VERSION 5.7 ;
  NOWIREEXTENSIONATPIN ON ;
  DIVIDERCHAR "/" ;
  BUSBITCHARS "[]" ;
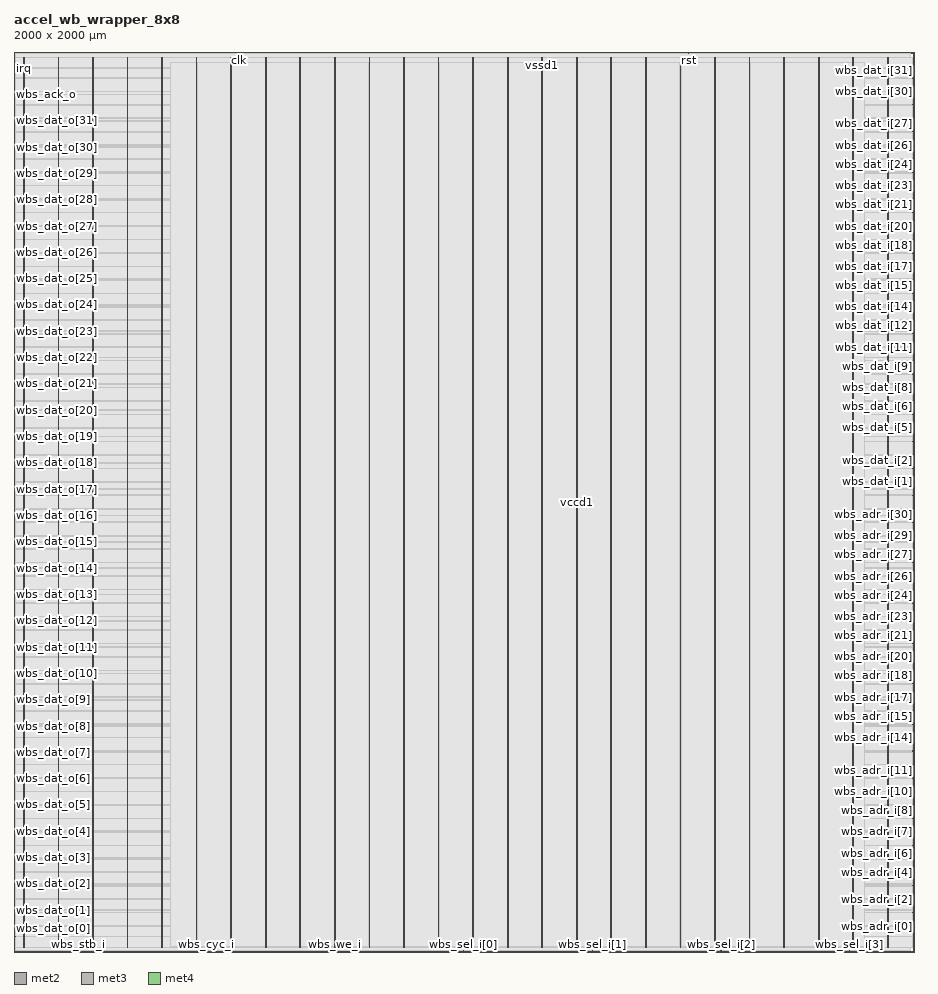
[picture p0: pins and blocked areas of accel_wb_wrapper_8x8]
MACRO accel_wb_wrapper_8x8
  CLASS BLOCK ;
  FOREIGN accel_wb_wrapper_8x8 ;
  ORIGIN 0.000 0.000 ;
  SIZE 2000.000 BY 2000.000 ;
  PIN clk
    DIRECTION INPUT ;
    USE SIGNAL ;
    ANTENNAGATEAREA 0.852000 ;
    ANTENNADIFFAREA 0.869400 ;
    PORT
      LAYER met2 ;
        RECT 499.650 1996.000 499.930 2000.000 ;
    END
  END clk
  PIN irq
    DIRECTION OUTPUT ;
    USE SIGNAL ;
    PORT
      LAYER met3 ;
        RECT 0.000 1963.880 4.000 1964.480 ;
    END
  END irq
  PIN rst
    DIRECTION INPUT ;
    USE SIGNAL ;
    ANTENNAGATEAREA 0.247500 ;
    PORT
      LAYER met2 ;
        RECT 1499.690 1996.000 1499.970 2000.000 ;
    END
  END rst
  PIN vccd1
    DIRECTION INOUT ;
    USE POWER ;
    PORT
      LAYER met4 ;
        RECT 21.040 10.640 22.640 1988.560 ;
    END
    PORT
      LAYER met4 ;
        RECT 174.640 10.640 176.240 1988.560 ;
    END
    PORT
      LAYER met4 ;
        RECT 328.240 10.640 329.840 1988.560 ;
    END
    PORT
      LAYER met4 ;
        RECT 481.840 10.640 483.440 1988.560 ;
    END
    PORT
      LAYER met4 ;
        RECT 635.440 10.640 637.040 1988.560 ;
    END
    PORT
      LAYER met4 ;
        RECT 789.040 10.640 790.640 1988.560 ;
    END
    PORT
      LAYER met4 ;
        RECT 942.640 10.640 944.240 1988.560 ;
    END
    PORT
      LAYER met4 ;
        RECT 1096.240 10.640 1097.840 1988.560 ;
    END
    PORT
      LAYER met4 ;
        RECT 1249.840 10.640 1251.440 1988.560 ;
    END
    PORT
      LAYER met4 ;
        RECT 1403.440 10.640 1405.040 1988.560 ;
    END
    PORT
      LAYER met4 ;
        RECT 1557.040 10.640 1558.640 1988.560 ;
    END
    PORT
      LAYER met4 ;
        RECT 1710.640 10.640 1712.240 1988.560 ;
    END
    PORT
      LAYER met4 ;
        RECT 1864.240 10.640 1865.840 1988.560 ;
    END
  END vccd1
  PIN vssd1
    DIRECTION INOUT ;
    USE GROUND ;
    PORT
      LAYER met4 ;
        RECT 97.840 10.640 99.440 1988.560 ;
    END
    PORT
      LAYER met4 ;
        RECT 251.440 10.640 253.040 1988.560 ;
    END
    PORT
      LAYER met4 ;
        RECT 405.040 10.640 406.640 1988.560 ;
    END
    PORT
      LAYER met4 ;
        RECT 558.640 10.640 560.240 1988.560 ;
    END
    PORT
      LAYER met4 ;
        RECT 712.240 10.640 713.840 1988.560 ;
    END
    PORT
      LAYER met4 ;
        RECT 865.840 10.640 867.440 1988.560 ;
    END
    PORT
      LAYER met4 ;
        RECT 1019.440 10.640 1021.040 1988.560 ;
    END
    PORT
      LAYER met4 ;
        RECT 1173.040 10.640 1174.640 1988.560 ;
    END
    PORT
      LAYER met4 ;
        RECT 1326.640 10.640 1328.240 1988.560 ;
    END
    PORT
      LAYER met4 ;
        RECT 1480.240 10.640 1481.840 1988.560 ;
    END
    PORT
      LAYER met4 ;
        RECT 1633.840 10.640 1635.440 1988.560 ;
    END
    PORT
      LAYER met4 ;
        RECT 1787.440 10.640 1789.040 1988.560 ;
    END
    PORT
      LAYER met4 ;
        RECT 1941.040 10.640 1942.640 1988.560 ;
    END
  END vssd1
  PIN wbs_ack_o
    DIRECTION OUTPUT ;
    USE SIGNAL ;
    ANTENNADIFFAREA 1.782000 ;
    PORT
      LAYER met3 ;
        RECT 0.000 1905.400 4.000 1906.000 ;
    END
  END wbs_ack_o
  PIN wbs_adr_i[0]
    DIRECTION INPUT ;
    USE SIGNAL ;
    ANTENNAGATEAREA 0.742500 ;
    PORT
      LAYER met3 ;
        RECT 1996.000 57.160 2000.000 57.760 ;
    END
  END wbs_adr_i[0]
  PIN wbs_adr_i[10]
    DIRECTION INPUT ;
    USE SIGNAL ;
    ANTENNAGATEAREA 0.196500 ;
    PORT
      LAYER met3 ;
        RECT 1996.000 356.360 2000.000 356.960 ;
    END
  END wbs_adr_i[10]
  PIN wbs_adr_i[11]
    DIRECTION INPUT ;
    USE SIGNAL ;
    ANTENNAGATEAREA 0.196500 ;
    PORT
      LAYER met3 ;
        RECT 1996.000 386.280 2000.000 386.880 ;
    END
  END wbs_adr_i[11]
  PIN wbs_adr_i[12]
    DIRECTION INPUT ;
    USE SIGNAL ;
    ANTENNAGATEAREA 0.196500 ;
    PORT
      LAYER met3 ;
        RECT 1996.000 416.200 2000.000 416.800 ;
    END
  END wbs_adr_i[12]
  PIN wbs_adr_i[13]
    DIRECTION INPUT ;
    USE SIGNAL ;
    ANTENNAGATEAREA 0.196500 ;
    PORT
      LAYER met3 ;
        RECT 1996.000 446.120 2000.000 446.720 ;
    END
  END wbs_adr_i[13]
  PIN wbs_adr_i[14]
    DIRECTION INPUT ;
    USE SIGNAL ;
    ANTENNAGATEAREA 0.196500 ;
    PORT
      LAYER met3 ;
        RECT 1996.000 476.040 2000.000 476.640 ;
    END
  END wbs_adr_i[14]
  PIN wbs_adr_i[15]
    DIRECTION INPUT ;
    USE SIGNAL ;
    ANTENNAGATEAREA 0.196500 ;
    PORT
      LAYER met3 ;
        RECT 1996.000 505.960 2000.000 506.560 ;
    END
  END wbs_adr_i[15]
  PIN wbs_adr_i[16]
    DIRECTION INPUT ;
    USE SIGNAL ;
    ANTENNAGATEAREA 0.196500 ;
    PORT
      LAYER met3 ;
        RECT 1996.000 535.880 2000.000 536.480 ;
    END
  END wbs_adr_i[16]
  PIN wbs_adr_i[17]
    DIRECTION INPUT ;
    USE SIGNAL ;
    ANTENNAGATEAREA 0.196500 ;
    PORT
      LAYER met3 ;
        RECT 1996.000 565.800 2000.000 566.400 ;
    END
  END wbs_adr_i[17]
  PIN wbs_adr_i[18]
    DIRECTION INPUT ;
    USE SIGNAL ;
    ANTENNAGATEAREA 0.196500 ;
    PORT
      LAYER met3 ;
        RECT 1996.000 595.720 2000.000 596.320 ;
    END
  END wbs_adr_i[18]
  PIN wbs_adr_i[19]
    DIRECTION INPUT ;
    USE SIGNAL ;
    ANTENNAGATEAREA 0.196500 ;
    PORT
      LAYER met3 ;
        RECT 1996.000 625.640 2000.000 626.240 ;
    END
  END wbs_adr_i[19]
  PIN wbs_adr_i[1]
    DIRECTION INPUT ;
    USE SIGNAL ;
    ANTENNAGATEAREA 0.495000 ;
    PORT
      LAYER met3 ;
        RECT 1996.000 87.080 2000.000 87.680 ;
    END
  END wbs_adr_i[1]
  PIN wbs_adr_i[20]
    DIRECTION INPUT ;
    USE SIGNAL ;
    ANTENNAGATEAREA 0.196500 ;
    PORT
      LAYER met3 ;
        RECT 1996.000 655.560 2000.000 656.160 ;
    END
  END wbs_adr_i[20]
  PIN wbs_adr_i[21]
    DIRECTION INPUT ;
    USE SIGNAL ;
    ANTENNAGATEAREA 0.196500 ;
    PORT
      LAYER met3 ;
        RECT 1996.000 685.480 2000.000 686.080 ;
    END
  END wbs_adr_i[21]
  PIN wbs_adr_i[22]
    DIRECTION INPUT ;
    USE SIGNAL ;
    ANTENNAGATEAREA 0.196500 ;
    PORT
      LAYER met3 ;
        RECT 1996.000 715.400 2000.000 716.000 ;
    END
  END wbs_adr_i[22]
  PIN wbs_adr_i[23]
    DIRECTION INPUT ;
    USE SIGNAL ;
    ANTENNAGATEAREA 0.196500 ;
    PORT
      LAYER met3 ;
        RECT 1996.000 745.320 2000.000 745.920 ;
    END
  END wbs_adr_i[23]
  PIN wbs_adr_i[24]
    DIRECTION INPUT ;
    USE SIGNAL ;
    ANTENNAGATEAREA 0.196500 ;
    PORT
      LAYER met3 ;
        RECT 1996.000 775.240 2000.000 775.840 ;
    END
  END wbs_adr_i[24]
  PIN wbs_adr_i[25]
    DIRECTION INPUT ;
    USE SIGNAL ;
    ANTENNAGATEAREA 0.196500 ;
    PORT
      LAYER met3 ;
        RECT 1996.000 805.160 2000.000 805.760 ;
    END
  END wbs_adr_i[25]
  PIN wbs_adr_i[26]
    DIRECTION INPUT ;
    USE SIGNAL ;
    ANTENNAGATEAREA 0.196500 ;
    PORT
      LAYER met3 ;
        RECT 1996.000 835.080 2000.000 835.680 ;
    END
  END wbs_adr_i[26]
  PIN wbs_adr_i[27]
    DIRECTION INPUT ;
    USE SIGNAL ;
    ANTENNAGATEAREA 0.196500 ;
    PORT
      LAYER met3 ;
        RECT 1996.000 865.000 2000.000 865.600 ;
    END
  END wbs_adr_i[27]
  PIN wbs_adr_i[28]
    DIRECTION INPUT ;
    USE SIGNAL ;
    ANTENNAGATEAREA 0.196500 ;
    PORT
      LAYER met3 ;
        RECT 1996.000 894.920 2000.000 895.520 ;
    END
  END wbs_adr_i[28]
  PIN wbs_adr_i[29]
    DIRECTION INPUT ;
    USE SIGNAL ;
    ANTENNAGATEAREA 0.213000 ;
    PORT
      LAYER met3 ;
        RECT 1996.000 924.840 2000.000 925.440 ;
    END
  END wbs_adr_i[29]
  PIN wbs_adr_i[2]
    DIRECTION INPUT ;
    USE SIGNAL ;
    ANTENNAGATEAREA 0.495000 ;
    PORT
      LAYER met3 ;
        RECT 1996.000 117.000 2000.000 117.600 ;
    END
  END wbs_adr_i[2]
  PIN wbs_adr_i[30]
    DIRECTION INPUT ;
    USE SIGNAL ;
    ANTENNAGATEAREA 0.247500 ;
    PORT
      LAYER met3 ;
        RECT 1996.000 954.760 2000.000 955.360 ;
    END
  END wbs_adr_i[30]
  PIN wbs_adr_i[31]
    DIRECTION INPUT ;
    USE SIGNAL ;
    ANTENNAGATEAREA 0.247500 ;
    PORT
      LAYER met3 ;
        RECT 1996.000 984.680 2000.000 985.280 ;
    END
  END wbs_adr_i[31]
  PIN wbs_adr_i[3]
    DIRECTION INPUT ;
    USE SIGNAL ;
    ANTENNAGATEAREA 0.495000 ;
    PORT
      LAYER met3 ;
        RECT 1996.000 146.920 2000.000 147.520 ;
    END
  END wbs_adr_i[3]
  PIN wbs_adr_i[4]
    DIRECTION INPUT ;
    USE SIGNAL ;
    ANTENNAGATEAREA 0.426000 ;
    PORT
      LAYER met3 ;
        RECT 1996.000 176.840 2000.000 177.440 ;
    END
  END wbs_adr_i[4]
  PIN wbs_adr_i[5]
    DIRECTION INPUT ;
    USE SIGNAL ;
    ANTENNAGATEAREA 0.426000 ;
    PORT
      LAYER met3 ;
        RECT 1996.000 206.760 2000.000 207.360 ;
    END
  END wbs_adr_i[5]
  PIN wbs_adr_i[6]
    DIRECTION INPUT ;
    USE SIGNAL ;
    ANTENNAGATEAREA 0.742500 ;
    PORT
      LAYER met3 ;
        RECT 1996.000 236.680 2000.000 237.280 ;
    END
  END wbs_adr_i[6]
  PIN wbs_adr_i[7]
    DIRECTION INPUT ;
    USE SIGNAL ;
    ANTENNAGATEAREA 0.742500 ;
    PORT
      LAYER met3 ;
        RECT 1996.000 266.600 2000.000 267.200 ;
    END
  END wbs_adr_i[7]
  PIN wbs_adr_i[8]
    DIRECTION INPUT ;
    USE SIGNAL ;
    ANTENNAGATEAREA 0.196500 ;
    PORT
      LAYER met3 ;
        RECT 1996.000 296.520 2000.000 297.120 ;
    END
  END wbs_adr_i[8]
  PIN wbs_adr_i[9]
    DIRECTION INPUT ;
    USE SIGNAL ;
    ANTENNAGATEAREA 0.196500 ;
    PORT
      LAYER met3 ;
        RECT 1996.000 326.440 2000.000 327.040 ;
    END
  END wbs_adr_i[9]
  PIN wbs_cyc_i
    DIRECTION INPUT ;
    USE SIGNAL ;
    ANTENNAGATEAREA 0.196500 ;
    PORT
      LAYER met2 ;
        RECT 428.350 0.000 428.630 4.000 ;
    END
  END wbs_cyc_i
  PIN wbs_dat_i[0]
    DIRECTION INPUT ;
    USE SIGNAL ;
    ANTENNAGATEAREA 0.196500 ;
    PORT
      LAYER met3 ;
        RECT 1996.000 1014.600 2000.000 1015.200 ;
    END
  END wbs_dat_i[0]
  PIN wbs_dat_i[10]
    DIRECTION INPUT ;
    USE SIGNAL ;
    ANTENNAGATEAREA 0.159000 ;
    PORT
      LAYER met3 ;
        RECT 1996.000 1313.800 2000.000 1314.400 ;
    END
  END wbs_dat_i[10]
  PIN wbs_dat_i[11]
    DIRECTION INPUT ;
    USE SIGNAL ;
    ANTENNAGATEAREA 0.159000 ;
    PORT
      LAYER met3 ;
        RECT 1996.000 1343.720 2000.000 1344.320 ;
    END
  END wbs_dat_i[11]
  PIN wbs_dat_i[12]
    DIRECTION INPUT ;
    USE SIGNAL ;
    ANTENNAGATEAREA 0.247500 ;
    PORT
      LAYER met3 ;
        RECT 1996.000 1373.640 2000.000 1374.240 ;
    END
  END wbs_dat_i[12]
  PIN wbs_dat_i[13]
    DIRECTION INPUT ;
    USE SIGNAL ;
    ANTENNAGATEAREA 0.213000 ;
    PORT
      LAYER met3 ;
        RECT 1996.000 1403.560 2000.000 1404.160 ;
    END
  END wbs_dat_i[13]
  PIN wbs_dat_i[14]
    DIRECTION INPUT ;
    USE SIGNAL ;
    ANTENNAGATEAREA 0.247500 ;
    PORT
      LAYER met3 ;
        RECT 1996.000 1433.480 2000.000 1434.080 ;
    END
  END wbs_dat_i[14]
  PIN wbs_dat_i[15]
    DIRECTION INPUT ;
    USE SIGNAL ;
    ANTENNAGATEAREA 0.213000 ;
    PORT
      LAYER met3 ;
        RECT 1996.000 1463.400 2000.000 1464.000 ;
    END
  END wbs_dat_i[15]
  PIN wbs_dat_i[16]
    DIRECTION INPUT ;
    USE SIGNAL ;
    ANTENNAGATEAREA 0.426000 ;
    PORT
      LAYER met3 ;
        RECT 1996.000 1493.320 2000.000 1493.920 ;
    END
  END wbs_dat_i[16]
  PIN wbs_dat_i[17]
    DIRECTION INPUT ;
    USE SIGNAL ;
    ANTENNAGATEAREA 0.247500 ;
    PORT
      LAYER met3 ;
        RECT 1996.000 1523.240 2000.000 1523.840 ;
    END
  END wbs_dat_i[17]
  PIN wbs_dat_i[18]
    DIRECTION INPUT ;
    USE SIGNAL ;
    ANTENNAGATEAREA 0.247500 ;
    PORT
      LAYER met3 ;
        RECT 1996.000 1553.160 2000.000 1553.760 ;
    END
  END wbs_dat_i[18]
  PIN wbs_dat_i[19]
    DIRECTION INPUT ;
    USE SIGNAL ;
    ANTENNAGATEAREA 0.247500 ;
    PORT
      LAYER met3 ;
        RECT 1996.000 1583.080 2000.000 1583.680 ;
    END
  END wbs_dat_i[19]
  PIN wbs_dat_i[1]
    DIRECTION INPUT ;
    USE SIGNAL ;
    ANTENNAGATEAREA 0.247500 ;
    PORT
      LAYER met3 ;
        RECT 1996.000 1044.520 2000.000 1045.120 ;
    END
  END wbs_dat_i[1]
  PIN wbs_dat_i[20]
    DIRECTION INPUT ;
    USE SIGNAL ;
    ANTENNAGATEAREA 0.426000 ;
    PORT
      LAYER met3 ;
        RECT 1996.000 1613.000 2000.000 1613.600 ;
    END
  END wbs_dat_i[20]
  PIN wbs_dat_i[21]
    DIRECTION INPUT ;
    USE SIGNAL ;
    ANTENNAGATEAREA 0.247500 ;
    PORT
      LAYER met3 ;
        RECT 1996.000 1642.920 2000.000 1643.520 ;
    END
  END wbs_dat_i[21]
  PIN wbs_dat_i[22]
    DIRECTION INPUT ;
    USE SIGNAL ;
    ANTENNAGATEAREA 0.426000 ;
    PORT
      LAYER met3 ;
        RECT 1996.000 1672.840 2000.000 1673.440 ;
    END
  END wbs_dat_i[22]
  PIN wbs_dat_i[23]
    DIRECTION INPUT ;
    USE SIGNAL ;
    ANTENNAGATEAREA 0.495000 ;
    PORT
      LAYER met3 ;
        RECT 1996.000 1702.760 2000.000 1703.360 ;
    END
  END wbs_dat_i[23]
  PIN wbs_dat_i[24]
    DIRECTION INPUT ;
    USE SIGNAL ;
    ANTENNAGATEAREA 0.247500 ;
    PORT
      LAYER met3 ;
        RECT 1996.000 1732.680 2000.000 1733.280 ;
    END
  END wbs_dat_i[24]
  PIN wbs_dat_i[25]
    DIRECTION INPUT ;
    USE SIGNAL ;
    ANTENNAGATEAREA 0.247500 ;
    PORT
      LAYER met3 ;
        RECT 1996.000 1762.600 2000.000 1763.200 ;
    END
  END wbs_dat_i[25]
  PIN wbs_dat_i[26]
    DIRECTION INPUT ;
    USE SIGNAL ;
    ANTENNAGATEAREA 0.426000 ;
    PORT
      LAYER met3 ;
        RECT 1996.000 1792.520 2000.000 1793.120 ;
    END
  END wbs_dat_i[26]
  PIN wbs_dat_i[27]
    DIRECTION INPUT ;
    USE SIGNAL ;
    ANTENNAGATEAREA 0.247500 ;
    PORT
      LAYER met3 ;
        RECT 1996.000 1822.440 2000.000 1823.040 ;
    END
  END wbs_dat_i[27]
  PIN wbs_dat_i[28]
    DIRECTION INPUT ;
    USE SIGNAL ;
    ANTENNAGATEAREA 0.495000 ;
    PORT
      LAYER met3 ;
        RECT 1996.000 1852.360 2000.000 1852.960 ;
    END
  END wbs_dat_i[28]
  PIN wbs_dat_i[29]
    DIRECTION INPUT ;
    USE SIGNAL ;
    ANTENNAGATEAREA 0.495000 ;
    PORT
      LAYER met3 ;
        RECT 1996.000 1882.280 2000.000 1882.880 ;
    END
  END wbs_dat_i[29]
  PIN wbs_dat_i[2]
    DIRECTION INPUT ;
    USE SIGNAL ;
    ANTENNAGATEAREA 0.247500 ;
    PORT
      LAYER met3 ;
        RECT 1996.000 1074.440 2000.000 1075.040 ;
    END
  END wbs_dat_i[2]
  PIN wbs_dat_i[30]
    DIRECTION INPUT ;
    USE SIGNAL ;
    ANTENNAGATEAREA 0.426000 ;
    PORT
      LAYER met3 ;
        RECT 1996.000 1912.200 2000.000 1912.800 ;
    END
  END wbs_dat_i[30]
  PIN wbs_dat_i[31]
    DIRECTION INPUT ;
    USE SIGNAL ;
    ANTENNAGATEAREA 0.426000 ;
    PORT
      LAYER met3 ;
        RECT 1996.000 1942.120 2000.000 1942.720 ;
    END
  END wbs_dat_i[31]
  PIN wbs_dat_i[3]
    DIRECTION INPUT ;
    USE SIGNAL ;
    ANTENNAGATEAREA 0.247500 ;
    PORT
      LAYER met3 ;
        RECT 1996.000 1104.360 2000.000 1104.960 ;
    END
  END wbs_dat_i[3]
  PIN wbs_dat_i[4]
    DIRECTION INPUT ;
    USE SIGNAL ;
    ANTENNAGATEAREA 0.159000 ;
    PORT
      LAYER met3 ;
        RECT 1996.000 1134.280 2000.000 1134.880 ;
    END
  END wbs_dat_i[4]
  PIN wbs_dat_i[5]
    DIRECTION INPUT ;
    USE SIGNAL ;
    ANTENNAGATEAREA 0.495000 ;
    PORT
      LAYER met3 ;
        RECT 1996.000 1164.200 2000.000 1164.800 ;
    END
  END wbs_dat_i[5]
  PIN wbs_dat_i[6]
    DIRECTION INPUT ;
    USE SIGNAL ;
    ANTENNAGATEAREA 0.159000 ;
    PORT
      LAYER met3 ;
        RECT 1996.000 1194.120 2000.000 1194.720 ;
    END
  END wbs_dat_i[6]
  PIN wbs_dat_i[7]
    DIRECTION INPUT ;
    USE SIGNAL ;
    ANTENNAGATEAREA 0.159000 ;
    PORT
      LAYER met3 ;
        RECT 1996.000 1224.040 2000.000 1224.640 ;
    END
  END wbs_dat_i[7]
  PIN wbs_dat_i[8]
    DIRECTION INPUT ;
    USE SIGNAL ;
    ANTENNAGATEAREA 0.213000 ;
    PORT
      LAYER met3 ;
        RECT 1996.000 1253.960 2000.000 1254.560 ;
    END
  END wbs_dat_i[8]
  PIN wbs_dat_i[9]
    DIRECTION INPUT ;
    USE SIGNAL ;
    ANTENNAGATEAREA 0.213000 ;
    PORT
      LAYER met3 ;
        RECT 1996.000 1283.880 2000.000 1284.480 ;
    END
  END wbs_dat_i[9]
  PIN wbs_dat_o[0]
    DIRECTION OUTPUT ;
    USE SIGNAL ;
    ANTENNADIFFAREA 1.782000 ;
    PORT
      LAYER met3 ;
        RECT 0.000 34.040 4.000 34.640 ;
    END
  END wbs_dat_o[0]
  PIN wbs_dat_o[10]
    DIRECTION OUTPUT ;
    USE SIGNAL ;
    ANTENNADIFFAREA 1.782000 ;
    PORT
      LAYER met3 ;
        RECT 0.000 618.840 4.000 619.440 ;
    END
  END wbs_dat_o[10]
  PIN wbs_dat_o[11]
    DIRECTION OUTPUT ;
    USE SIGNAL ;
    ANTENNADIFFAREA 1.782000 ;
    PORT
      LAYER met3 ;
        RECT 0.000 677.320 4.000 677.920 ;
    END
  END wbs_dat_o[11]
  PIN wbs_dat_o[12]
    DIRECTION OUTPUT ;
    USE SIGNAL ;
    ANTENNADIFFAREA 1.782000 ;
    PORT
      LAYER met3 ;
        RECT 0.000 735.800 4.000 736.400 ;
    END
  END wbs_dat_o[12]
  PIN wbs_dat_o[13]
    DIRECTION OUTPUT ;
    USE SIGNAL ;
    ANTENNADIFFAREA 1.782000 ;
    PORT
      LAYER met3 ;
        RECT 0.000 794.280 4.000 794.880 ;
    END
  END wbs_dat_o[13]
  PIN wbs_dat_o[14]
    DIRECTION OUTPUT ;
    USE SIGNAL ;
    ANTENNADIFFAREA 1.782000 ;
    PORT
      LAYER met3 ;
        RECT 0.000 852.760 4.000 853.360 ;
    END
  END wbs_dat_o[14]
  PIN wbs_dat_o[15]
    DIRECTION OUTPUT ;
    USE SIGNAL ;
    ANTENNADIFFAREA 1.782000 ;
    PORT
      LAYER met3 ;
        RECT 0.000 911.240 4.000 911.840 ;
    END
  END wbs_dat_o[15]
  PIN wbs_dat_o[16]
    DIRECTION OUTPUT ;
    USE SIGNAL ;
    ANTENNADIFFAREA 1.782000 ;
    PORT
      LAYER met3 ;
        RECT 0.000 969.720 4.000 970.320 ;
    END
  END wbs_dat_o[16]
  PIN wbs_dat_o[17]
    DIRECTION OUTPUT ;
    USE SIGNAL ;
    ANTENNADIFFAREA 1.782000 ;
    PORT
      LAYER met3 ;
        RECT 0.000 1028.200 4.000 1028.800 ;
    END
  END wbs_dat_o[17]
  PIN wbs_dat_o[18]
    DIRECTION OUTPUT ;
    USE SIGNAL ;
    ANTENNADIFFAREA 1.782000 ;
    PORT
      LAYER met3 ;
        RECT 0.000 1086.680 4.000 1087.280 ;
    END
  END wbs_dat_o[18]
  PIN wbs_dat_o[19]
    DIRECTION OUTPUT ;
    USE SIGNAL ;
    ANTENNADIFFAREA 1.782000 ;
    PORT
      LAYER met3 ;
        RECT 0.000 1145.160 4.000 1145.760 ;
    END
  END wbs_dat_o[19]
  PIN wbs_dat_o[1]
    DIRECTION OUTPUT ;
    USE SIGNAL ;
    ANTENNADIFFAREA 1.782000 ;
    PORT
      LAYER met3 ;
        RECT 0.000 92.520 4.000 93.120 ;
    END
  END wbs_dat_o[1]
  PIN wbs_dat_o[20]
    DIRECTION OUTPUT ;
    USE SIGNAL ;
    ANTENNADIFFAREA 1.782000 ;
    PORT
      LAYER met3 ;
        RECT 0.000 1203.640 4.000 1204.240 ;
    END
  END wbs_dat_o[20]
  PIN wbs_dat_o[21]
    DIRECTION OUTPUT ;
    USE SIGNAL ;
    ANTENNADIFFAREA 1.782000 ;
    PORT
      LAYER met3 ;
        RECT 0.000 1262.120 4.000 1262.720 ;
    END
  END wbs_dat_o[21]
  PIN wbs_dat_o[22]
    DIRECTION OUTPUT ;
    USE SIGNAL ;
    ANTENNADIFFAREA 1.782000 ;
    PORT
      LAYER met3 ;
        RECT 0.000 1320.600 4.000 1321.200 ;
    END
  END wbs_dat_o[22]
  PIN wbs_dat_o[23]
    DIRECTION OUTPUT ;
    USE SIGNAL ;
    ANTENNADIFFAREA 1.782000 ;
    PORT
      LAYER met3 ;
        RECT 0.000 1379.080 4.000 1379.680 ;
    END
  END wbs_dat_o[23]
  PIN wbs_dat_o[24]
    DIRECTION OUTPUT ;
    USE SIGNAL ;
    ANTENNADIFFAREA 1.782000 ;
    PORT
      LAYER met3 ;
        RECT 0.000 1437.560 4.000 1438.160 ;
    END
  END wbs_dat_o[24]
  PIN wbs_dat_o[25]
    DIRECTION OUTPUT ;
    USE SIGNAL ;
    ANTENNADIFFAREA 1.782000 ;
    PORT
      LAYER met3 ;
        RECT 0.000 1496.040 4.000 1496.640 ;
    END
  END wbs_dat_o[25]
  PIN wbs_dat_o[26]
    DIRECTION OUTPUT ;
    USE SIGNAL ;
    ANTENNADIFFAREA 1.782000 ;
    PORT
      LAYER met3 ;
        RECT 0.000 1554.520 4.000 1555.120 ;
    END
  END wbs_dat_o[26]
  PIN wbs_dat_o[27]
    DIRECTION OUTPUT ;
    USE SIGNAL ;
    ANTENNADIFFAREA 1.782000 ;
    PORT
      LAYER met3 ;
        RECT 0.000 1613.000 4.000 1613.600 ;
    END
  END wbs_dat_o[27]
  PIN wbs_dat_o[28]
    DIRECTION OUTPUT ;
    USE SIGNAL ;
    ANTENNADIFFAREA 1.782000 ;
    PORT
      LAYER met3 ;
        RECT 0.000 1671.480 4.000 1672.080 ;
    END
  END wbs_dat_o[28]
  PIN wbs_dat_o[29]
    DIRECTION OUTPUT ;
    USE SIGNAL ;
    ANTENNADIFFAREA 1.782000 ;
    PORT
      LAYER met3 ;
        RECT 0.000 1729.960 4.000 1730.560 ;
    END
  END wbs_dat_o[29]
  PIN wbs_dat_o[2]
    DIRECTION OUTPUT ;
    USE SIGNAL ;
    ANTENNADIFFAREA 1.782000 ;
    PORT
      LAYER met3 ;
        RECT 0.000 151.000 4.000 151.600 ;
    END
  END wbs_dat_o[2]
  PIN wbs_dat_o[30]
    DIRECTION OUTPUT ;
    USE SIGNAL ;
    ANTENNADIFFAREA 1.782000 ;
    PORT
      LAYER met3 ;
        RECT 0.000 1788.440 4.000 1789.040 ;
    END
  END wbs_dat_o[30]
  PIN wbs_dat_o[31]
    DIRECTION OUTPUT ;
    USE SIGNAL ;
    ANTENNADIFFAREA 1.782000 ;
    PORT
      LAYER met3 ;
        RECT 0.000 1846.920 4.000 1847.520 ;
    END
  END wbs_dat_o[31]
  PIN wbs_dat_o[3]
    DIRECTION OUTPUT ;
    USE SIGNAL ;
    ANTENNADIFFAREA 1.782000 ;
    PORT
      LAYER met3 ;
        RECT 0.000 209.480 4.000 210.080 ;
    END
  END wbs_dat_o[3]
  PIN wbs_dat_o[4]
    DIRECTION OUTPUT ;
    USE SIGNAL ;
    ANTENNADIFFAREA 1.782000 ;
    PORT
      LAYER met3 ;
        RECT 0.000 267.960 4.000 268.560 ;
    END
  END wbs_dat_o[4]
  PIN wbs_dat_o[5]
    DIRECTION OUTPUT ;
    USE SIGNAL ;
    ANTENNADIFFAREA 1.782000 ;
    PORT
      LAYER met3 ;
        RECT 0.000 326.440 4.000 327.040 ;
    END
  END wbs_dat_o[5]
  PIN wbs_dat_o[6]
    DIRECTION OUTPUT ;
    USE SIGNAL ;
    ANTENNADIFFAREA 1.782000 ;
    PORT
      LAYER met3 ;
        RECT 0.000 384.920 4.000 385.520 ;
    END
  END wbs_dat_o[6]
  PIN wbs_dat_o[7]
    DIRECTION OUTPUT ;
    USE SIGNAL ;
    ANTENNADIFFAREA 1.782000 ;
    PORT
      LAYER met3 ;
        RECT 0.000 443.400 4.000 444.000 ;
    END
  END wbs_dat_o[7]
  PIN wbs_dat_o[8]
    DIRECTION OUTPUT ;
    USE SIGNAL ;
    ANTENNADIFFAREA 1.782000 ;
    PORT
      LAYER met3 ;
        RECT 0.000 501.880 4.000 502.480 ;
    END
  END wbs_dat_o[8]
  PIN wbs_dat_o[9]
    DIRECTION OUTPUT ;
    USE SIGNAL ;
    ANTENNADIFFAREA 1.782000 ;
    PORT
      LAYER met3 ;
        RECT 0.000 560.360 4.000 560.960 ;
    END
  END wbs_dat_o[9]
  PIN wbs_sel_i[0]
    DIRECTION INPUT ;
    USE SIGNAL ;
    ANTENNAGATEAREA 0.213000 ;
    PORT
      LAYER met2 ;
        RECT 999.670 0.000 999.950 4.000 ;
    END
  END wbs_sel_i[0]
  PIN wbs_sel_i[1]
    DIRECTION INPUT ;
    USE SIGNAL ;
    ANTENNAGATEAREA 0.742500 ;
    PORT
      LAYER met2 ;
        RECT 1285.330 0.000 1285.610 4.000 ;
    END
  END wbs_sel_i[1]
  PIN wbs_sel_i[2]
    DIRECTION INPUT ;
    USE SIGNAL ;
    ANTENNAGATEAREA 0.495000 ;
    PORT
      LAYER met2 ;
        RECT 1570.990 0.000 1571.270 4.000 ;
    END
  END wbs_sel_i[2]
  PIN wbs_sel_i[3]
    DIRECTION INPUT ;
    USE SIGNAL ;
    ANTENNAGATEAREA 0.990000 ;
    PORT
      LAYER met2 ;
        RECT 1856.650 0.000 1856.930 4.000 ;
    END
  END wbs_sel_i[3]
  PIN wbs_stb_i
    DIRECTION INPUT ;
    USE SIGNAL ;
    ANTENNAGATEAREA 0.159000 ;
    PORT
      LAYER met2 ;
        RECT 142.690 0.000 142.970 4.000 ;
    END
  END wbs_stb_i
  PIN wbs_we_i
    DIRECTION INPUT ;
    USE SIGNAL ;
    ANTENNAGATEAREA 0.990000 ;
    PORT
      LAYER met2 ;
        RECT 714.010 0.000 714.290 4.000 ;
    END
  END wbs_we_i
  OBS
      LAYER nwell ;
        RECT 5.330 10.795 1994.290 1988.510 ;
      LAYER li1 ;
        RECT 5.520 10.795 1994.100 1988.405 ;
      LAYER met1 ;
        RECT 4.210 10.640 1994.100 1988.560 ;
      LAYER met2 ;
        RECT 4.230 1995.720 499.370 1996.000 ;
        RECT 500.210 1995.720 1499.410 1996.000 ;
        RECT 1500.250 1995.720 1992.630 1996.000 ;
        RECT 4.230 4.280 1992.630 1995.720 ;
        RECT 4.230 4.000 142.410 4.280 ;
        RECT 143.250 4.000 428.070 4.280 ;
        RECT 428.910 4.000 713.730 4.280 ;
        RECT 714.570 4.000 999.390 4.280 ;
        RECT 1000.230 4.000 1285.050 4.280 ;
        RECT 1285.890 4.000 1570.710 4.280 ;
        RECT 1571.550 4.000 1856.370 4.280 ;
        RECT 1857.210 4.000 1992.630 4.280 ;
      LAYER met3 ;
        RECT 3.990 1964.880 1996.000 1988.485 ;
        RECT 4.400 1963.480 1996.000 1964.880 ;
        RECT 3.990 1943.120 1996.000 1963.480 ;
        RECT 3.990 1941.720 1995.600 1943.120 ;
        RECT 3.990 1913.200 1996.000 1941.720 ;
        RECT 3.990 1911.800 1995.600 1913.200 ;
        RECT 3.990 1906.400 1996.000 1911.800 ;
        RECT 4.400 1905.000 1996.000 1906.400 ;
        RECT 3.990 1883.280 1996.000 1905.000 ;
        RECT 3.990 1881.880 1995.600 1883.280 ;
        RECT 3.990 1853.360 1996.000 1881.880 ;
        RECT 3.990 1851.960 1995.600 1853.360 ;
        RECT 3.990 1847.920 1996.000 1851.960 ;
        RECT 4.400 1846.520 1996.000 1847.920 ;
        RECT 3.990 1823.440 1996.000 1846.520 ;
        RECT 3.990 1822.040 1995.600 1823.440 ;
        RECT 3.990 1793.520 1996.000 1822.040 ;
        RECT 3.990 1792.120 1995.600 1793.520 ;
        RECT 3.990 1789.440 1996.000 1792.120 ;
        RECT 4.400 1788.040 1996.000 1789.440 ;
        RECT 3.990 1763.600 1996.000 1788.040 ;
        RECT 3.990 1762.200 1995.600 1763.600 ;
        RECT 3.990 1733.680 1996.000 1762.200 ;
        RECT 3.990 1732.280 1995.600 1733.680 ;
        RECT 3.990 1730.960 1996.000 1732.280 ;
        RECT 4.400 1729.560 1996.000 1730.960 ;
        RECT 3.990 1703.760 1996.000 1729.560 ;
        RECT 3.990 1702.360 1995.600 1703.760 ;
        RECT 3.990 1673.840 1996.000 1702.360 ;
        RECT 3.990 1672.480 1995.600 1673.840 ;
        RECT 4.400 1672.440 1995.600 1672.480 ;
        RECT 4.400 1671.080 1996.000 1672.440 ;
        RECT 3.990 1643.920 1996.000 1671.080 ;
        RECT 3.990 1642.520 1995.600 1643.920 ;
        RECT 3.990 1614.000 1996.000 1642.520 ;
        RECT 4.400 1612.600 1995.600 1614.000 ;
        RECT 3.990 1584.080 1996.000 1612.600 ;
        RECT 3.990 1582.680 1995.600 1584.080 ;
        RECT 3.990 1555.520 1996.000 1582.680 ;
        RECT 4.400 1554.160 1996.000 1555.520 ;
        RECT 4.400 1554.120 1995.600 1554.160 ;
        RECT 3.990 1552.760 1995.600 1554.120 ;
        RECT 3.990 1524.240 1996.000 1552.760 ;
        RECT 3.990 1522.840 1995.600 1524.240 ;
        RECT 3.990 1497.040 1996.000 1522.840 ;
        RECT 4.400 1495.640 1996.000 1497.040 ;
        RECT 3.990 1494.320 1996.000 1495.640 ;
        RECT 3.990 1492.920 1995.600 1494.320 ;
        RECT 3.990 1464.400 1996.000 1492.920 ;
        RECT 3.990 1463.000 1995.600 1464.400 ;
        RECT 3.990 1438.560 1996.000 1463.000 ;
        RECT 4.400 1437.160 1996.000 1438.560 ;
        RECT 3.990 1434.480 1996.000 1437.160 ;
        RECT 3.990 1433.080 1995.600 1434.480 ;
        RECT 3.990 1404.560 1996.000 1433.080 ;
        RECT 3.990 1403.160 1995.600 1404.560 ;
        RECT 3.990 1380.080 1996.000 1403.160 ;
        RECT 4.400 1378.680 1996.000 1380.080 ;
        RECT 3.990 1374.640 1996.000 1378.680 ;
        RECT 3.990 1373.240 1995.600 1374.640 ;
        RECT 3.990 1344.720 1996.000 1373.240 ;
        RECT 3.990 1343.320 1995.600 1344.720 ;
        RECT 3.990 1321.600 1996.000 1343.320 ;
        RECT 4.400 1320.200 1996.000 1321.600 ;
        RECT 3.990 1314.800 1996.000 1320.200 ;
        RECT 3.990 1313.400 1995.600 1314.800 ;
        RECT 3.990 1284.880 1996.000 1313.400 ;
        RECT 3.990 1283.480 1995.600 1284.880 ;
        RECT 3.990 1263.120 1996.000 1283.480 ;
        RECT 4.400 1261.720 1996.000 1263.120 ;
        RECT 3.990 1254.960 1996.000 1261.720 ;
        RECT 3.990 1253.560 1995.600 1254.960 ;
        RECT 3.990 1225.040 1996.000 1253.560 ;
        RECT 3.990 1223.640 1995.600 1225.040 ;
        RECT 3.990 1204.640 1996.000 1223.640 ;
        RECT 4.400 1203.240 1996.000 1204.640 ;
        RECT 3.990 1195.120 1996.000 1203.240 ;
        RECT 3.990 1193.720 1995.600 1195.120 ;
        RECT 3.990 1165.200 1996.000 1193.720 ;
        RECT 3.990 1163.800 1995.600 1165.200 ;
        RECT 3.990 1146.160 1996.000 1163.800 ;
        RECT 4.400 1144.760 1996.000 1146.160 ;
        RECT 3.990 1135.280 1996.000 1144.760 ;
        RECT 3.990 1133.880 1995.600 1135.280 ;
        RECT 3.990 1105.360 1996.000 1133.880 ;
        RECT 3.990 1103.960 1995.600 1105.360 ;
        RECT 3.990 1087.680 1996.000 1103.960 ;
        RECT 4.400 1086.280 1996.000 1087.680 ;
        RECT 3.990 1075.440 1996.000 1086.280 ;
        RECT 3.990 1074.040 1995.600 1075.440 ;
        RECT 3.990 1045.520 1996.000 1074.040 ;
        RECT 3.990 1044.120 1995.600 1045.520 ;
        RECT 3.990 1029.200 1996.000 1044.120 ;
        RECT 4.400 1027.800 1996.000 1029.200 ;
        RECT 3.990 1015.600 1996.000 1027.800 ;
        RECT 3.990 1014.200 1995.600 1015.600 ;
        RECT 3.990 985.680 1996.000 1014.200 ;
        RECT 3.990 984.280 1995.600 985.680 ;
        RECT 3.990 970.720 1996.000 984.280 ;
        RECT 4.400 969.320 1996.000 970.720 ;
        RECT 3.990 955.760 1996.000 969.320 ;
        RECT 3.990 954.360 1995.600 955.760 ;
        RECT 3.990 925.840 1996.000 954.360 ;
        RECT 3.990 924.440 1995.600 925.840 ;
        RECT 3.990 912.240 1996.000 924.440 ;
        RECT 4.400 910.840 1996.000 912.240 ;
        RECT 3.990 895.920 1996.000 910.840 ;
        RECT 3.990 894.520 1995.600 895.920 ;
        RECT 3.990 866.000 1996.000 894.520 ;
        RECT 3.990 864.600 1995.600 866.000 ;
        RECT 3.990 853.760 1996.000 864.600 ;
        RECT 4.400 852.360 1996.000 853.760 ;
        RECT 3.990 836.080 1996.000 852.360 ;
        RECT 3.990 834.680 1995.600 836.080 ;
        RECT 3.990 806.160 1996.000 834.680 ;
        RECT 3.990 804.760 1995.600 806.160 ;
        RECT 3.990 795.280 1996.000 804.760 ;
        RECT 4.400 793.880 1996.000 795.280 ;
        RECT 3.990 776.240 1996.000 793.880 ;
        RECT 3.990 774.840 1995.600 776.240 ;
        RECT 3.990 746.320 1996.000 774.840 ;
        RECT 3.990 744.920 1995.600 746.320 ;
        RECT 3.990 736.800 1996.000 744.920 ;
        RECT 4.400 735.400 1996.000 736.800 ;
        RECT 3.990 716.400 1996.000 735.400 ;
        RECT 3.990 715.000 1995.600 716.400 ;
        RECT 3.990 686.480 1996.000 715.000 ;
        RECT 3.990 685.080 1995.600 686.480 ;
        RECT 3.990 678.320 1996.000 685.080 ;
        RECT 4.400 676.920 1996.000 678.320 ;
        RECT 3.990 656.560 1996.000 676.920 ;
        RECT 3.990 655.160 1995.600 656.560 ;
        RECT 3.990 626.640 1996.000 655.160 ;
        RECT 3.990 625.240 1995.600 626.640 ;
        RECT 3.990 619.840 1996.000 625.240 ;
        RECT 4.400 618.440 1996.000 619.840 ;
        RECT 3.990 596.720 1996.000 618.440 ;
        RECT 3.990 595.320 1995.600 596.720 ;
        RECT 3.990 566.800 1996.000 595.320 ;
        RECT 3.990 565.400 1995.600 566.800 ;
        RECT 3.990 561.360 1996.000 565.400 ;
        RECT 4.400 559.960 1996.000 561.360 ;
        RECT 3.990 536.880 1996.000 559.960 ;
        RECT 3.990 535.480 1995.600 536.880 ;
        RECT 3.990 506.960 1996.000 535.480 ;
        RECT 3.990 505.560 1995.600 506.960 ;
        RECT 3.990 502.880 1996.000 505.560 ;
        RECT 4.400 501.480 1996.000 502.880 ;
        RECT 3.990 477.040 1996.000 501.480 ;
        RECT 3.990 475.640 1995.600 477.040 ;
        RECT 3.990 447.120 1996.000 475.640 ;
        RECT 3.990 445.720 1995.600 447.120 ;
        RECT 3.990 444.400 1996.000 445.720 ;
        RECT 4.400 443.000 1996.000 444.400 ;
        RECT 3.990 417.200 1996.000 443.000 ;
        RECT 3.990 415.800 1995.600 417.200 ;
        RECT 3.990 387.280 1996.000 415.800 ;
        RECT 3.990 385.920 1995.600 387.280 ;
        RECT 4.400 385.880 1995.600 385.920 ;
        RECT 4.400 384.520 1996.000 385.880 ;
        RECT 3.990 357.360 1996.000 384.520 ;
        RECT 3.990 355.960 1995.600 357.360 ;
        RECT 3.990 327.440 1996.000 355.960 ;
        RECT 4.400 326.040 1995.600 327.440 ;
        RECT 3.990 297.520 1996.000 326.040 ;
        RECT 3.990 296.120 1995.600 297.520 ;
        RECT 3.990 268.960 1996.000 296.120 ;
        RECT 4.400 267.600 1996.000 268.960 ;
        RECT 4.400 267.560 1995.600 267.600 ;
        RECT 3.990 266.200 1995.600 267.560 ;
        RECT 3.990 237.680 1996.000 266.200 ;
        RECT 3.990 236.280 1995.600 237.680 ;
        RECT 3.990 210.480 1996.000 236.280 ;
        RECT 4.400 209.080 1996.000 210.480 ;
        RECT 3.990 207.760 1996.000 209.080 ;
        RECT 3.990 206.360 1995.600 207.760 ;
        RECT 3.990 177.840 1996.000 206.360 ;
        RECT 3.990 176.440 1995.600 177.840 ;
        RECT 3.990 152.000 1996.000 176.440 ;
        RECT 4.400 150.600 1996.000 152.000 ;
        RECT 3.990 147.920 1996.000 150.600 ;
        RECT 3.990 146.520 1995.600 147.920 ;
        RECT 3.990 118.000 1996.000 146.520 ;
        RECT 3.990 116.600 1995.600 118.000 ;
        RECT 3.990 93.520 1996.000 116.600 ;
        RECT 4.400 92.120 1996.000 93.520 ;
        RECT 3.990 88.080 1996.000 92.120 ;
        RECT 3.990 86.680 1995.600 88.080 ;
        RECT 3.990 58.160 1996.000 86.680 ;
        RECT 3.990 56.760 1995.600 58.160 ;
        RECT 3.990 35.040 1996.000 56.760 ;
        RECT 4.400 33.640 1996.000 35.040 ;
        RECT 3.990 10.715 1996.000 33.640 ;
      LAYER met4 ;
        RECT 347.135 11.735 404.640 1976.585 ;
        RECT 407.040 11.735 481.440 1976.585 ;
        RECT 483.840 11.735 558.240 1976.585 ;
        RECT 560.640 11.735 635.040 1976.585 ;
        RECT 637.440 11.735 711.840 1976.585 ;
        RECT 714.240 11.735 788.640 1976.585 ;
        RECT 791.040 11.735 865.440 1976.585 ;
        RECT 867.840 11.735 942.240 1976.585 ;
        RECT 944.640 11.735 1019.040 1976.585 ;
        RECT 1021.440 11.735 1095.840 1976.585 ;
        RECT 1098.240 11.735 1172.640 1976.585 ;
        RECT 1175.040 11.735 1249.440 1976.585 ;
        RECT 1251.840 11.735 1326.240 1976.585 ;
        RECT 1328.640 11.735 1403.040 1976.585 ;
        RECT 1405.440 11.735 1479.840 1976.585 ;
        RECT 1482.240 11.735 1556.640 1976.585 ;
        RECT 1559.040 11.735 1633.440 1976.585 ;
        RECT 1635.840 11.735 1710.240 1976.585 ;
        RECT 1712.640 11.735 1787.040 1976.585 ;
        RECT 1789.440 11.735 1863.840 1976.585 ;
        RECT 1866.240 11.735 1890.305 1976.585 ;
  END
END accel_wb_wrapper_8x8
END LIBRARY

